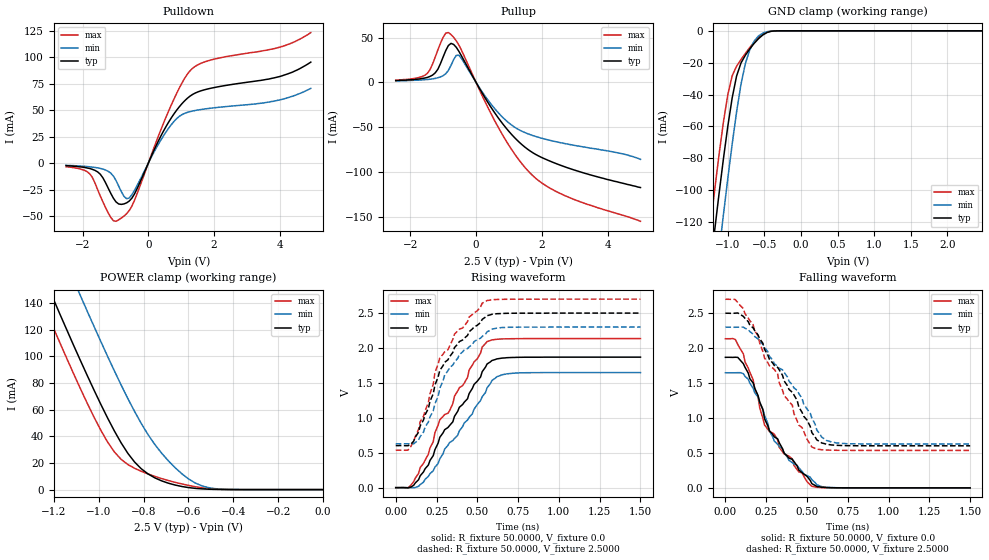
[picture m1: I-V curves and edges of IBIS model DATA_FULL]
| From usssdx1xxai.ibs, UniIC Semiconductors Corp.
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|   Model DATA_FULL
[Model]  DATA_FULL
Model_type   I/O
Polarity   Non-Inverting
Enable   Active-High
Vinl =   940.000mV
Vinh =   1.560V
Vmeas =   1.250V
Vref =   1.250V
Cref =   30.000pF
Rref =   50.000Ohm
C_comp   2.2640pF   2.2480pF   2.2810pF
[Temperature Range]   25.0000   85.0000   -40.0000
[Voltage Range]   2.5000V   2.3000V   2.7000V
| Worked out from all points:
|   slope of the pulldown table from 0 to 0.375 V, typ, clamps not added: 14.9 ohm
|   slope of the pullup table from 0 to 0.375 V, typ, clamps not added: 16.1 ohm
|   GND clamp passes 1 mA (typ) near -0.46 V on its own axis
|   POWER clamp passes 1 mA (typ) near -0.57 V on its own axis
|   rising waveform, R_fixture 50.0000, V_fixture 0.0: 20-80 % time 280ps typ, 282ps min, 268ps max; typ from 0 V to 1.87 V
|   rising waveform, R_fixture 50.0000, V_fixture 2.5000: 20-80 % time 240ps typ, 215ps min, 233ps max; typ from 0.602 V to 2.5 V
|   falling waveform, R_fixture 50.0000, V_fixture 0.0: 20-80 % time 251ps typ, 238ps min, 263ps max; typ from 1.87 V to 0 V
|   falling waveform, R_fixture 50.0000, V_fixture 2.5000: 20-80 % time 282ps typ, 283ps min, 260ps max; typ from 2.5 V to 0.602 V
[Pulldown]
|Voltage   I(typ)   I(min)   I(max)
-2.5V     -2.3mA     -2mA       -3.3mA
-1.78V    -5mA       -3.4mA     -10mA
-1.46V    -10.4mA    -4.9mA     -30.9mA
-1.14V    -28.5mA    -9.4mA     -51.14mA
-980mV    -36.59mA   -16.4mA    -54.83mA
-740mV    -38.42mA   -31.22mA   -49.91mA
-580mV    -35.73mA   -32.78mA   -44.65mA
620mV     38.87mA    33.1mA     49.4mA
1.02V     56.08mA    45.78mA    75.52mA
1.34V     64.79mA    49.2mA     89.38mA
3.98V     81.7mA     59.7mA     109.4mA
4.94V     95.4mA     70.6mA     123.3mA
[Pullup]
|Voltage   I(typ)   I(min)   I(max)
-2.44V    1.9mA      1.6mA      2.4mA
-1.48V    5.4mA      3.1mA      10mA
-1.16V    14.5mA     5mA        36mA
-1V       28.2mA     7.3mA      50.21mA
-840mV    41.02mA    13.2mA     55.52mA
-680mV    42.28mA    25.32mA    50.22mA
-520mV    34.55mA    30.19mA    41.58mA
680mV     -39.91mA   -34.13mA   -50.54mA
1.24V     -64.34mA   -51.67mA   -83.48mA
1.72V     -78.55mA   -59.42mA   -104.1mA
2.84V     -96.22mA   -69.45mA   -128.8mA
5V        -117.6mA   -86.1mA    -155.3mA
[GND_clamp]
|Voltage   I(typ)   I(min)   I(max)
-2.5V     -683.1mA   -721.3mA   -659.9mA
-1.24V    -149mA     -187mA     -123.6mA
-1.18V    -125.4mA   -162.7mA   -100.2mA
-1.12V    -102.4mA   -138.9mA   -77.87mA
-1.06V    -80.41mA   -115.5mA   -57.35mA
-1V       -59.95mA   -92.78mA   -40.06mA
-940mV    -42.05mA   -71.05mA   -28.21mA
-880mV    -28.39mA   -50.93mA   -22.22mA
-760mV    -15.32mA   -20.58mA   -14.17mA
-700mV    -11.37mA   -12mA      -10.48mA
-520mV    -2.567mA   -1.422mA   -2.005mA
2.48V     19.82nA    197.4nA    2.769nA
[POWER_clamp]
|Voltage   I(typ)   I(min)   I(max)
-2.49V    671mA      720.4mA    651.7mA
-1.26V    165.8mA    215.5mA    144.3mA
-1.2V     142.3mA    191.8mA    120.7mA
-1.08V    96.37mA    145mA      75.23mA
-960mV    53.65mA    99.93mA    35.62mA
-900mV    35.09mA    78.55mA    22.71mA
-840mV    20.7mA     58.65mA    16mA
-750mV    8.845mA    33.93mA    9.957mA
-630mV    2.359mA    11.98mA    4.279mA
-570mV    942.1uA    4.996mA    2.169mA
-480mV    155.9uA    702.6uA    387.2uA
0V        21.05nA    13.45nA    5.53nA
[Ramp]
| variable   typ   min   max
dV/dt_r  1.1214/0.2791n   0.9888/0.2790n   1.2810/0.2688n
dV/dt_f  1.1387/0.2788n   1.0032/0.2797n   1.2983/0.2571n
R_load = 50.0000
[Rising Waveform]
R_fixture= 50.0000
V_fixture= 0.0
V_fixture_min= 0.0
V_fixture_max= 0.0
|time   V(typ)   V(min)   V(max)
0s        0V         0V         0V
75.76ps   -3.298mV   209.9uV    -1.716mV
170ps     224.4mV    77.99mV    346.4mV
270ps     720.7mV    412.5mV    972.7mV
330ps     889.6mV    645.3mV    1.102V
360ps     1.021V     704.4mV    1.31V
560ps     1.771V     1.43V      2.092V
620ps     1.844V     1.589V     2.125V
710ps     1.864V     1.637V     2.133V
1.5ns     1.869V     1.648V     2.135V
[Rising Waveform]
R_fixture= 50.0000
V_fixture= 2.5000
V_fixture_min= 2.3000
V_fixture_max= 2.7000
|time   V(typ)   V(min)   V(max)
0s        602.1mV    628mV      536.1mV
75.76ps   600.5mV    627.2mV    537.2mV
140ps     795.1mV    684.1mV    834.4mV
230ps     1.345V     1.1V       1.481V
240ps     1.467V     1.2V       1.646V
270ps     1.679V     1.423V     1.857V
390ps     2.092V     1.905V     2.27V
530ps     2.41V      2.166V     2.641V
650ps     2.495V     2.293V     2.697V
1.5ns     2.5V       2.3V       2.7V
[Falling Waveform]
R_fixture= 50.0000
V_fixture= 0.0
V_fixture_min= 0.0
V_fixture_max= 0.0
|time   V(typ)   V(min)   V(max)
0s        1.869V     1.648V     2.135V
60.61ps   1.87V      1.648V     2.125V
140ps     1.644V     1.555V     1.714V
200ps     1.323V     1.3V       1.308V
240ps     988.9mV    1.035V     899mV
300ps     729.1mV    668.3mV    765.6mV
360ps     496.7mV    500.7mV    483.3mV
530ps     59.69mV    117mV      22.25mV
650ps     2.335mV    3.845mV    1.138mV
1.5ns     0V         0V         0V
[Falling Waveform]
R_fixture= 50.0000
V_fixture= 2.5000
V_fixture_min= 2.3000
V_fixture_max= 2.7000
|time   V(typ)   V(min)   V(max)
0s        2.5V       2.3V       2.7V
60.61ps   2.501V     2.299V     2.696V
170ps     2.291V     2.201V     2.335V
240ps     1.982V     2.009V     1.858V
320ps     1.725V     1.74V      1.631V
360ps     1.531V     1.651V     1.32V
530ps     790.5mV    999.2mV    584.4mV
590ps     643.1mV    726mV      545.3mV
680ps     609.2mV    643.6mV    537.9mV
1.5ns     602.1mV    628mV      536.1mV
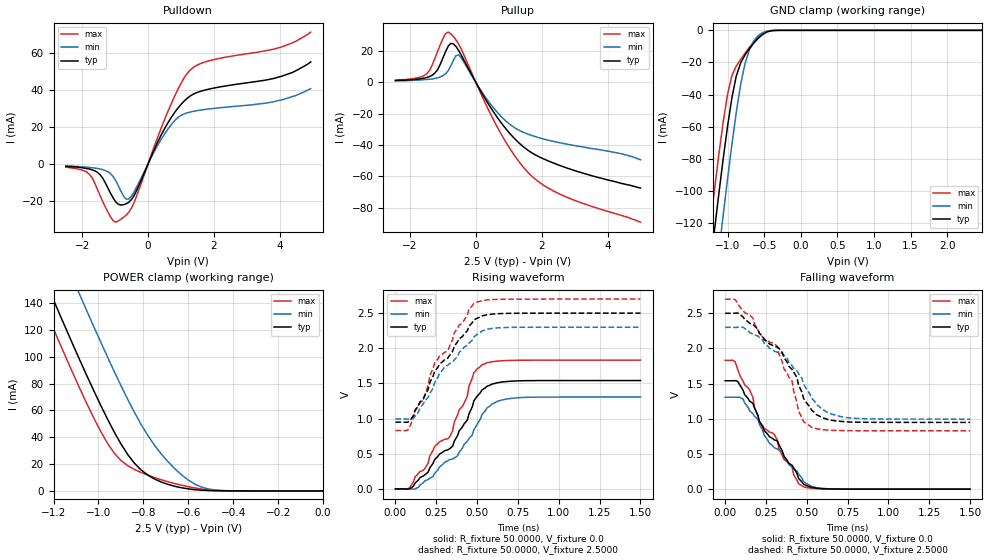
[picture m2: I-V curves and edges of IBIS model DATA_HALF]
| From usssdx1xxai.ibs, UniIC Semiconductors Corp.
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|   Model DATA_HALF
[Model]  DATA_HALF
Model_type   I/O
Polarity   Non-Inverting
Enable   Active-High
Vinl =   940.000mV
Vinh =   1.560V
Vmeas =   1.250V
Vref =   1.250V
Cref =   30.000pF
Rref =   50.000Ohm
C_comp   2.2640pF   2.2480pF   2.2810pF
[Temperature Range]   25.0000   85.0000   -40.0000
[Voltage Range]   2.5000V   2.3000V   2.7000V
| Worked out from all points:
|   slope of the pulldown table from 0 to 0.375 V, typ, clamps not added: 25.4 ohm
|   slope of the pullup table from 0 to 0.375 V, typ, clamps not added: 27.5 ohm
|   GND clamp passes 1 mA (typ) near -0.46 V on its own axis
|   POWER clamp passes 1 mA (typ) near -0.57 V on its own axis
|   rising waveform, R_fixture 50.0000, V_fixture 0.0: 20-80 % time 265ps typ, 271ps min, 251ps max; typ from 0 V to 1.54 V
|   rising waveform, R_fixture 50.0000, V_fixture 2.5000: 20-80 % time 256ps typ, 257ps min, 244ps max; typ from 0.949 V to 2.5 V
|   falling waveform, R_fixture 50.0000, V_fixture 0.0: 20-80 % time 257ps typ, 261ps min, 261ps max; typ from 1.54 V to 0 V
|   falling waveform, R_fixture 50.0000, V_fixture 2.5000: 20-80 % time 269ps typ, 286ps min, 257ps max; typ from 2.5 V to 0.949 V
[Pulldown]
|Voltage   I(typ)   I(min)   I(max)
-2.5V     -1.3mA     -1.2mA     -1.8mA
-1.78V    -2.8mA     -2mA       -5.7mA
-1.46V    -5.9mA     -2.8mA     -17.1mA
-1.14V    -15.9mA    -5.3mA     -28.64mA
-900mV    -21.91mA   -12mA      -30.77mA
-580mV    -20.65mA   -18.95mA   -25.98mA
540mV     20.23mA    17.2mA     25.62mA
860mV     29.02mA    24.28mA    38.53mA
1.26V     36.38mA    27.86mA    50.31mA
1.9V      40.53mA    29.71mA    55.83mA
4.06V     47.3mA     34.5mA     63.1mA
4.94V     55mA       40.6mA     71.1mA
[Pullup]
|Voltage   I(typ)   I(min)   I(max)
-2.44V    1.1mA      900uA      1.4mA
-1.48V    3.1mA      1.8mA      5.6mA
-1.16V    8mA        2.8mA      19.7mA
-920mV    19.5mA     5.37mA     31.02mA
-840mV    22.97mA    7.35mA     32.02mA
-680mV    24.48mA    14.02mA    29.24mA
-520mV    20.23mA    17.49mA    24.41mA
680mV     -23.26mA   -19.81mA   -29.63mA
1.16V     -35.58mA   -28.74mA   -46.26mA
1.64V     -44.21mA   -33.54mA   -58.69mA
2.68V     -54.09mA   -39.15mA   -72.6mA
5V        -67.5mA    -49.5mA    -89.3mA
[GND_clamp]
|Voltage   I(typ)   I(min)   I(max)
-2.5V     -683.1mA   -721.3mA   -659.9mA
-1.24V    -149mA     -187mA     -123.6mA
-1.18V    -125.4mA   -162.7mA   -100.2mA
-1.12V    -102.4mA   -138.9mA   -77.87mA
-1.06V    -80.41mA   -115.5mA   -57.35mA
-1V       -59.95mA   -92.78mA   -40.06mA
-940mV    -42.05mA   -71.05mA   -28.21mA
-880mV    -28.39mA   -50.93mA   -22.22mA
-760mV    -15.32mA   -20.58mA   -14.17mA
-700mV    -11.37mA   -12mA      -10.48mA
-520mV    -2.567mA   -1.422mA   -2.005mA
2.48V     19.82nA    197.4nA    2.769nA
[POWER_clamp]
|Voltage   I(typ)   I(min)   I(max)
-2.49V    671mA      720.4mA    651.7mA
-1.26V    165.8mA    215.5mA    144.3mA
-1.2V     142.3mA    191.8mA    120.7mA
-1.08V    96.37mA    145mA      75.23mA
-960mV    53.65mA    99.93mA    35.62mA
-900mV    35.09mA    78.55mA    22.71mA
-840mV    20.7mA     58.65mA    16mA
-750mV    8.845mA    33.93mA    9.957mA
-630mV    2.359mA    11.98mA    4.279mA
-570mV    942.1uA    4.996mA    2.169mA
-480mV    155.9uA    702.6uA    387.2uA
0V        21.05nA    13.45nA    5.53nA
[Ramp]
| variable   typ   min   max
dV/dt_r  0.9246/0.2643n   0.7842/0.2696n   1.0986/0.2554n
dV/dt_f  0.9306/0.2690n   0.7827/0.2817n   1.1221/0.2541n
R_load = 50.0000
[Rising Waveform]
R_fixture= 50.0000
V_fixture= 0.0
V_fixture_min= 0.0
V_fixture_max= 0.0
|time   V(typ)   V(min)   V(max)
0s        0V         0V         0V
75.76ps   -4.006mV   257.6uV    -2.603mV
180ps     200.9mV    114.2mV    288mV
240ps     418.2mV    220.3mV    604.5mV
330ps     568.4mV    415mV      733mV
440ps     978.5mV    677.2mV    1.317V
480ps     1.251V     837.4mV    1.652V
530ps     1.407V     1.057V     1.765V
710ps     1.532V     1.288V     1.828V
1.5ns     1.541V     1.307V     1.831V
[Rising Waveform]
R_fixture= 50.0000
V_fixture= 2.5000
V_fixture_min= 2.3000
V_fixture_max= 2.7000
|time   V(typ)   V(min)   V(max)
0s        949mV      995.5mV    829.9mV
75.76ps   948.9mV    992.7mV    834.4mV
120ps     1.12V      1.034V     1.11V
170ps     1.279V     1.207V     1.262V
240ps     1.672V     1.512V     1.79V
320ps     1.859V     1.758V     1.964V
360ps     2.029V     1.835V     2.22V
480ps     2.402V     2.16V      2.637V
640ps     2.493V     2.292V     2.696V
1.5ns     2.5V       2.3V       2.7V
[Falling Waveform]
R_fixture= 50.0000
V_fixture= 0.0
V_fixture_min= 0.0
V_fixture_max= 0.0
|time   V(typ)   V(min)   V(max)
0s        1.541V     1.307V     1.831V
60.61ps   1.543V     1.307V     1.813V
110ps     1.406V     1.279V     1.535V
170ps     1.22V      1.071V     1.306V
210ps     961.6mV    921.5mV    961mV
300ps     701.4mV    590.5mV    781.3mV
360ps     465.4mV    470.7mV    423.5mV
480ps     70.89mV    109.4mV    32.8mV
620ps     4.617mV    6.487mV    2.095mV
1.5ns     -719.4nV   0V         0V
[Falling Waveform]
R_fixture= 50.0000
V_fixture= 2.5000
V_fixture_min= 2.3000
V_fixture_max= 2.7000
|time   V(typ)   V(min)   V(max)
0s        2.5V       2.3V       2.7V
60.61ps   2.501V     2.299V     2.697V
170ps     2.343V     2.204V     2.434V
210ps     2.217V     2.156V     2.207V
320ps     2.019V     1.947V     2.03V
410ps     1.702V     1.756V     1.535V
450ps     1.479V     1.642V     1.106V
530ps     1.121V     1.291V     879.5mV
740ps     957.2mV    1.019V     831.3mV
1.5ns     949mV      995.5mV    829.9mV
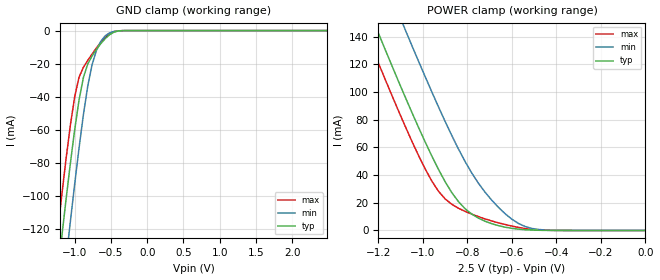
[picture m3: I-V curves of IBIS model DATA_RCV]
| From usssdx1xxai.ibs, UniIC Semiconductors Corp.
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|   Model DATA_RCV
[Model]  DATA_RCV
Model_type Input
Polarity   Non-Inverting
Vinl =   940.000mV
Vinh =   1.560V
C_comp   2.2640pF   2.2480pF   2.2810pF
[Temperature Range]   25.0000   85.0000   -40.0000
[Voltage Range]   2.5000V   2.3000V   2.7000V
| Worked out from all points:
|   GND clamp passes 1 mA (typ) near -0.46 V on its own axis
|   POWER clamp passes 1 mA (typ) near -0.57 V on its own axis
[GND_clamp]
|Voltage   I(typ)   I(min)   I(max)
-2.5V     -683.1mA   -721.3mA   -659.9mA
-1.24V    -149mA     -187mA     -123.6mA
-1.18V    -125.4mA   -162.7mA   -100.2mA
-1.12V    -102.4mA   -138.9mA   -77.87mA
-1.06V    -80.41mA   -115.5mA   -57.35mA
-1V       -59.95mA   -92.78mA   -40.06mA
-940mV    -42.05mA   -71.05mA   -28.21mA
-880mV    -28.39mA   -50.93mA   -22.22mA
-760mV    -15.32mA   -20.58mA   -14.17mA
-700mV    -11.37mA   -12mA      -10.48mA
-520mV    -2.567mA   -1.422mA   -2.005mA
2.48V     19.82nA    197.4nA    2.769nA
[POWER_clamp]
|Voltage   I(typ)   I(min)   I(max)
-2.49V    671mA      720.4mA    651.7mA
-1.26V    165.8mA    215.5mA    144.3mA
-1.2V     142.3mA    191.8mA    120.7mA
-1.08V    96.37mA    145mA      75.23mA
-960mV    53.65mA    99.93mA    35.62mA
-900mV    35.09mA    78.55mA    22.71mA
-840mV    20.7mA     58.65mA    16mA
-750mV    8.845mA    33.93mA    9.957mA
-630mV    2.359mA    11.98mA    4.279mA
-570mV    942.1uA    4.996mA    2.169mA
-480mV    155.9uA    702.6uA    387.2uA
0V        21.05nA    13.45nA    5.53nA
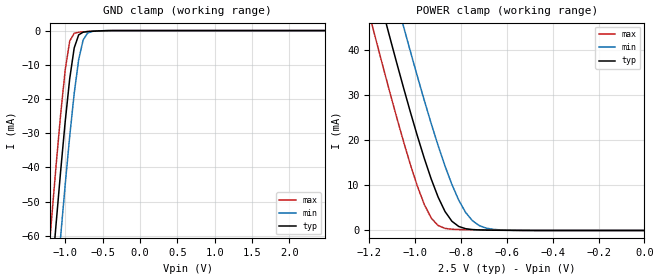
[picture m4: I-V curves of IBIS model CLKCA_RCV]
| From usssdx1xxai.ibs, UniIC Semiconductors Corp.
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|   Model CLKCA_RCV
[Model]  CLKCA_RCV
Model_type Input
Polarity   Non-Inverting
Vinl =   940.000mV
Vinh =   1.560V
C_comp   0.9200pF   0.8940pF   0.9290pF
[Temperature Range]   25.0000   85.0000   -40.0000
[Voltage Range]   2.5000V   2.3000V   2.7000V
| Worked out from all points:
|   GND clamp passes 1 mA (typ) near -0.80 V on its own axis
|   POWER clamp passes 1 mA (typ) near -0.81 V on its own axis
[GND_clamp]
|Voltage   I(typ)   I(min)   I(max)
-2.5V     -448.9mA   -467.1mA   -433.3mA
-1.24V    -87.9mA    -107.5mA   -70.59mA
-1.18V    -71.75mA   -91.32mA   -54.48mA
-1.12V    -55.99mA   -75.42mA   -38.9mA
-1.06V    -40.81mA   -59.91mA   -24.23mA
-1V       -26.57mA   -44.98mA   -11.44mA
-940mV    -14.08mA   -30.94mA   -3.07mA
-880mV    -5.084mA   -18.39mA   -767.8uA
-820mV    -1.257mA   -8.498mA   -478.8uA
-760mV    -458.7uA   -2.729mA   -375.1uA
-640mV    -199.4uA   -240.4uA   -205.9uA
2.48V     17.21nA    6.962nA    2.304nA
[POWER_clamp]
|Voltage   I(typ)   I(min)   I(max)
-2.49V    329.6mA    342.4mA    318.5mA
-1.2V     60.32mA    74.16mA    48.04mA
-1.17V    54.42mA    68.25mA    42.14mA
-1.11V    42.81mA    56.59mA    30.59mA
-1.05V    31.57mA    45.19mA    19.61mA
-990mV    20.94mA    34.17mA    9.785mA
-930mV    11.43mA    23.75mA    2.756mA
-870mV    4.231mA    14.34mA    466.4uA
-840mV    2.06mA     10.24mA    274.6uA
-750mV    202.6uA    2.159mA    148uA
-630mV    43.47uA    130.3uA    68.7uA
0V        18.39nA    1.267nA    4.914nA
